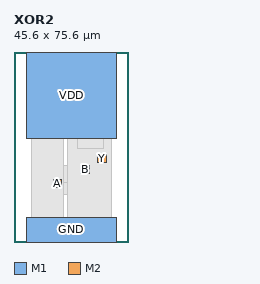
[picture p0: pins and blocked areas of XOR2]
MACRO XOR2
  CLASS CORE ;
  ORIGIN 0 0 ;
  SIZE 45.600 BY 75.600 ;
  SYMMETRY X Y ;
  SITE TR1um_access_site ;
  PIN VDD
    DIRECTION INOUT ;
    USE POWER ;
    PORT
      LAYER M1 ;
        RECT 5.000 41.000 40.600 75.600 ;
    END
  END VDD
  PIN GND
    DIRECTION INOUT ;
    USE GROUND ;
    PORT
      LAYER M1 ;
        RECT 5.000 0.000 40.600 9.800 ;
    END
  END GND
  PIN A
    DIRECTION INPUT ;
    USE SIGNAL ;
    PORT
      LAYER M2 ;
        RECT 15.600 21.600 19.000 25.000 ;
    END
  END A
  PIN B
    DIRECTION INPUT ;
    USE SIGNAL ;
    PORT
      LAYER M2 ;
        RECT 26.600 27.100 30.000 30.500 ;
    END
  END B
  PIN Y
    DIRECTION OUTPUT ;
    USE SIGNAL ;
    PORT
      LAYER M2 ;
        RECT 33.400 31.600 36.800 35.000 ;
    END
  END Y
  OBS
    LAYER M1 ;
      RECT 29.100 6.400 31.700 9.800 ;
    LAYER M1 ;
      RECT 10.300 19.000 32.900 25.000 ;
    LAYER M1 ;
      RECT 15.900 23.800 30.000 30.500 ;
    LAYER M1 ;
      RECT 13.100 41.000 15.700 51.200 ;
    LAYER M1 ;
      RECT 7.000 6.400 19.700 51.200 ;
    LAYER M1 ;
      RECT 21.100 6.400 38.600 51.200 ;
    LAYER M1 ;
      RECT 25.100 37.400 35.700 51.200 ;
    LAYER V1 ;
      RECT 16.600 22.600 18.000 24.000 ;
    LAYER V1 ;
      RECT 27.600 28.100 29.000 29.500 ;
    LAYER V1 ;
      RECT 34.400 32.600 35.800 34.000 ;
  END
END XOR2
